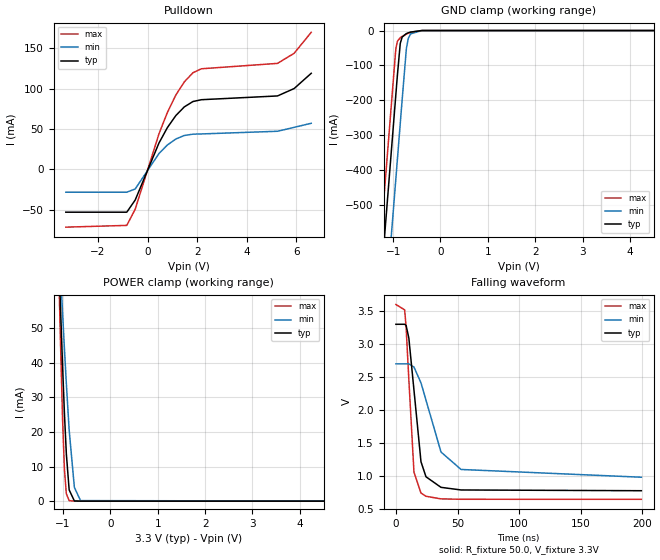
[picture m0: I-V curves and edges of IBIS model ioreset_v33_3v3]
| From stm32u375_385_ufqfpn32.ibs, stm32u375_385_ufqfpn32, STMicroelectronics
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[Model]   ioreset_v33_3v3
Model_type I/O_open_drain
Polarity   Inverting
Enable   Active-Low
| CAP_THRESHOLD on pad IOFT is "UDTCAPC" :
| Rising=30.0% of vddiom   Falling=70.0% of vddiom
| C_comp min and max val. don't necessarily correlate with the min and max pvt
| but are the smallest and greatest pad capacitance found.
| var   typ   min   max
C_comp   3.44597pF  3.36550pF  3.47178pF
|C_comp_pulldown   3.44597pF  3.36550pF  3.47178pF
Vinl = 1.35V
Vinh = 1.8V
Vmeas = 1.65V   | Reference voltage for timing measurements
Cref  = 50.0pF   | Timing specification test load capacitance value
Rref  = 1.0MOhm   | Timing specification test load resistance value
Vref  = 1.815V   | Timing specification test load voltage
[Model Spec]
| TIME_THRESHOLD on pin ZIV33M is "CMOS" :
| Rising=50.0% of vddiom   Falling=50.0% of vddiom
Vinl 1.27450V 1.06550V 1.35950V
Vinh 1.78050V 1.50550V 1.88450V
| variable   typ   min   max
[Temperature Range] 25.0 130.0 -40.0
| variable   typ   min   max
[Voltage Range] 3.3V 2.7V 3.6V
| variable   typ   min   max
[POWER Clamp Reference] 3.3V 2.7V 3.6V
| variable   typ   min   max
[GND Clamp Reference] 0V 0V 0V
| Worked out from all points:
|   slope of the pulldown table from 0 to 0.495 V, typ, clamps not added: 14.3 ohm
|   GND clamp passes 1 mA (typ) near -0.50 V on its own axis
|   POWER clamp passes 1 mA (typ) near -0.83 V on its own axis
|   falling waveform, R_fixture 50.0, V_fixture 3.3V: 20-80 % time 7.65ns typ, 16.7ns min, 4.97ns max; typ from 3.3 V to 0.776 V
[POWER Clamp]
-3.3V     1.126A     769.5mA    1.647A
-1.1V     75.38mA    79.63mA    73.18mA
-1.09V    71.2mA     76.8mA     67.14mA
-1.08V    67.05mA    73.98mA    61.2mA
-1.06V    58.89mA    68.38mA    49.67mA
-1.01V    39.47mA    54.71mA    24.03mA
-970mV    25.49mA    44.18mA    9.257mA
-930mV    13.81mA    34.16mA    2.168mA
-870mV    3.251mA    20.56mA    140.6uA
-760mV    67.19uA    3.98mA     739.7nA
-630mV    518.4nA    149.1uA    1.697nA
6.6V      0A         0A         0A
[GND Clamp]
-3.3V     -4.191A    -4.432A    -4.059A
-1.25V    -706mA     -946.8mA   -573.6mA
-950mV    -196mA     -436.8mA   -63.62mA
-940mV    -179mA     -419.8mA   -50.25mA
-910mV    -128mA     -368.8mA   -31.04mA
-850mV    -37.36mA   -266.8mA   -20.51mA
-810mV    -18.78mA   -198.8mA   -16.87mA
-720mV    -8.728mA   -51.28mA   -10.11mA
-680mV    -6.628mA   -22.6mA    -7.591mA
-630mV    -4.504mA   -9.469mA   -4.918mA
-400mV    -113.2uA   -367.7uA   -46.12uA
6.6V      1.003nA    32.07nA    797.8pA
| variable   typ   min   max
[Pullup Reference] 3.3V 2.7V 3.6V
| variable   typ   min   max
[Pulldown Reference] 0V 0V 0V
[Pulldown]
-3.3V     -53.27mA   -28.52mA   -71.84mA
-840mV    -53.27mA   -28.52mA   -69.65mA
-500mV    -38.18mA   -24.47mA   -49.51mA
460mV     32.61mA    19.53mA    43.99mA
800mV     51.7mA     30.09mA    70.55mA
1.14V     66.56mA    37.47mA    92mA
1.48V     77.24mA    41.82mA    108.3mA
1.83V     83.91mA    43.43mA    119.6mA
2.17V     86.16mA    43.73mA    124.5mA
5.24V     90.84mA    47.04mA    131.2mA
5.91V     100mA      51.87mA    143.7mA
6.6V      118.9mA    56.96mA    169.7mA
[Ramp]
dV/dt_r 1.51608V/235.12231ps 1.02368V/320.87969ps 1.74832V/215.46196ps
dV/dt_f 1.51461V/7.58441ns 1.03188V/16.42984ns 1.77303V/4.95318ns
R_load = 50.0
| Removed startup time: 0s 0s 0s  .
| Removed end time: 99.99us.
|[Rising Waveform]
|R_fixture   = 50.0
|V_fixture   = 3.3V
|V_fixture_min = 2.7V
|V_fixture_max = 3.6V
|  0s  775.65286mV  980.19224mV  645.13996mV
|  20.0ns  775.65286mV  980.19224mV  645.13996mV
|  30.0ns  775.65285mV  980.19224mV  645.13996mV
|  2.04us  775.65285mV  980.19224mV  645.13996mV
|  4.08us  775.65285mV  980.19224mV  645.13996mV
|  6.12us  775.65285mV  980.19224mV  645.13996mV
|  8.16us  775.65285mV  980.19224mV  645.13996mV
|  10.2us  775.65285mV  980.19224mV  645.13996mV
|  12.24us  775.65285mV  980.19224mV  645.13996mV
|  14.29us  775.65285mV  980.19224mV  645.13996mV
|  16.33us  775.65285mV  980.19224mV  645.13996mV
|  18.37us  775.65285mV  980.19224mV  645.13996mV
|  20.41us  775.65285mV  980.19224mV  645.13996mV
|  22.45us  775.65285mV  980.19224mV  645.13996mV
|  23.36us  775.65285mV  980.19224mV  645.13996mV
|  23.37us  775.65285mV  980.19224mV  3.59916V
|  23.38us  775.65285mV  980.19224mV  3.59993V
|  23.39us  775.65285mV  980.19224mV  3.59996V
|  23.4us  775.65285mV  980.19224mV  3.59998V
|  23.41us  775.65285mV  980.19224mV  3.59998V
|  23.42us  775.65285mV  980.19224mV  3.59999V
|  23.49us  775.65285mV  980.19224mV  3.59999V
|  23.5us  775.65285mV  980.19224mV  3.60000V
|  24.49us  775.65285mV  980.19224mV  3.60000V
|  25.03us  775.65285mV  980.19224mV  3.60000V
|  26.53us  775.65285mV  980.19224mV  3.60000V
|  28.57us  775.65285mV  980.19224mV  3.60000V
|  30.61us  775.65285mV  980.19224mV  3.60000V
|  32.65us  775.65285mV  980.19224mV  3.60000V
|  32.95us  775.65285mV  980.19224mV  3.60000V
|  32.96us  775.65286mV  980.19224mV  3.60000V
|  32.97us  775.65291mV  980.19224mV  3.60000V
|  32.98us  3.29976V  980.19224mV  3.60000V
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[Falling Waveform]
R_fixture   = 50.0
V_fixture   = 3.3V
V_fixture_min = 2.7V
V_fixture_max = 3.6V
0s        3.3V       2.7V       3.6V
7.1ns     3.3V       2.7V       3.518V
8.25ns    3.284V     2.7V       3.262V
10.5ns    3.089V     2.7V       2.456V
14.65ns   2.301V     2.651V     1.057V
20.35ns   1.215V     2.411V     739.7mV
24.4ns    987mV      2.15V      691.4mV
36.6ns    826.9mV    1.362V     651.9mV
52.9ns    787.1mV    1.098V     646mV
199.3ns   775.7mV    980.3mV    645.1mV
